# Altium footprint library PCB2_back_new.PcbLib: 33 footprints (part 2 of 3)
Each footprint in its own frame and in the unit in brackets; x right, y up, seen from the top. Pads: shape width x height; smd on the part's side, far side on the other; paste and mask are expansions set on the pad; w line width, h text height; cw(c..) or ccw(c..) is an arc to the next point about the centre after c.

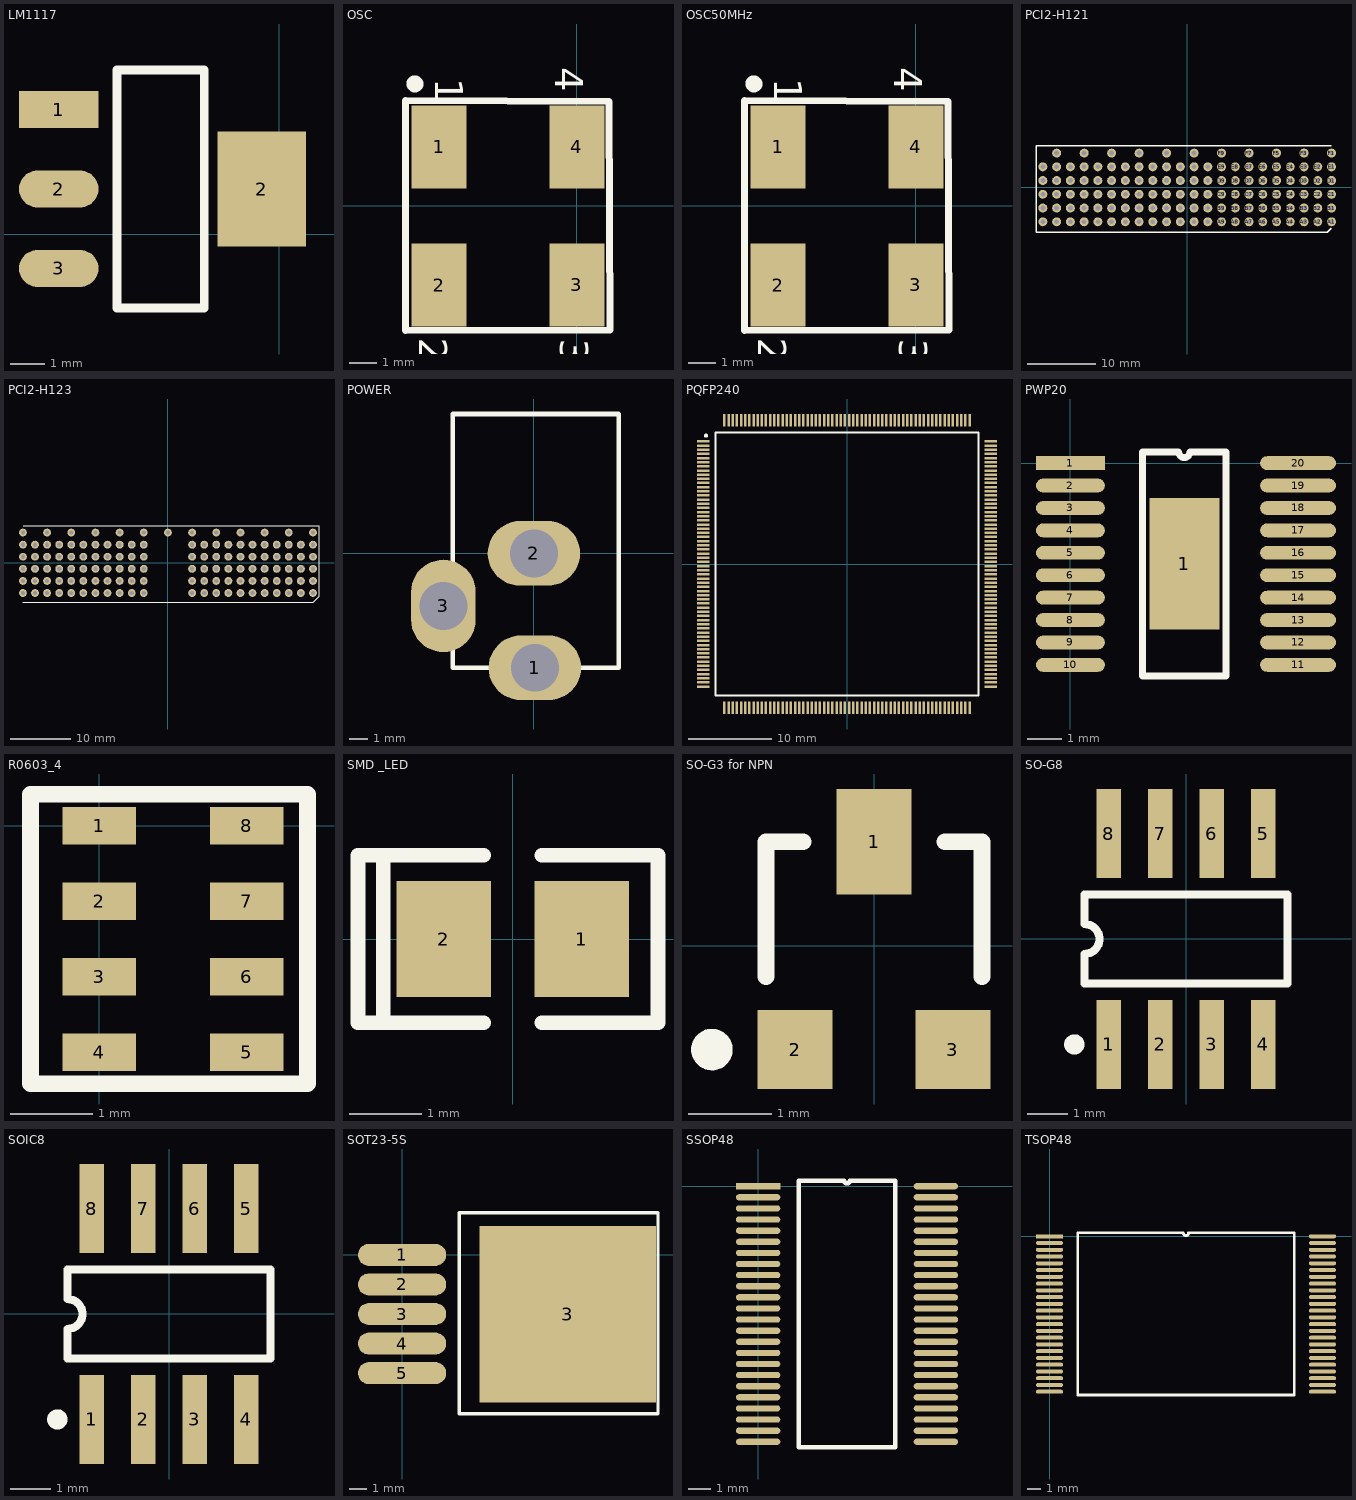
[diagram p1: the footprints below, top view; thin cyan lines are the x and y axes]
## LM1117 [mil]
pads (4):
  rect 90x42 smd: 1(-250,141)
  oval 90x42 smd: 2(-250,51) 3(-250,-39)
  rect 100x130 smd: 2(-20,51)
Top Overlay:
  lines w10: -99,186 -184,186 -184,-84 -85,-84 -85,186 -97.5,186

## OSC [mm]
height 3.5
pads (4):
  rect 2x3 smd: 1(-5,2.134) 2(-5,-2.87) 3(0,-2.866) 4(0,2.134)
Top Overlay:
  circle w0.5: c-5.873,4.42 r0.057
  lines w0.254: -6.223,-4.521 -6.223,3.81 1.168,3.785 1.194,-4.496 -6.223,-4.521
  text "4" at -0.787,5.029 h1.02
  text "3" at -0.61,-4.826 h1.02
  text "2" at -5.715,-4.775 h1.02
  text "1" at -5.131,4.623 h1.02

## OSC50MHz [mm] "for 50MHz"
height 3.5
pads (4):
  rect 2x3 smd: 1(-5,2.134) 2(-5,-2.87) 3(0,-2.866) 4(0,2.134)
Top Overlay:
  circle w0.5: c-5.873,4.42 r0.057
  lines w0.254: -6.223,-4.521 -6.223,3.81 1.168,3.785 1.194,-4.496 -6.223,-4.521
  text "4" at -0.787,5.029 h1.02
  text "3" at -0.61,-4.826 h1.02
  text "2" at -5.715,-4.775 h1.02
  text "1" at -5.131,4.623 h1.02

## PCI2-H121 [mm]
pads (121):
  round 1.3 hole 0.7: A1(21,-5) A2(19,-5) A3(17,-5) A4(15,-5) A5(13,-5) A6(11,-5) A7(9,-5) A8(7,-5) A9(5,-5) A10(3,-5) A11(1,-5) A12(-1,-5) A13(-3,-5) A14(-5,-5) A15(-7,-5) A16(-9,-5) A17(-11,-5) A18(-13,-5) A19(-15,-5) A20(-17,-5) A21(-19,-5) A22(-21,-5) B1(21,-3) B2(19,-3) B3(17,-3) B4(15,-3) B5(13,-3) B6(11,-3) B7(9,-3) B8(7,-3) B9(5,-3) B10(3,-3) B11(1,-3) B12(-1,-3) B13(-3,-3) B14(-5,-3) B15(-7,-3) B16(-9,-3) B17(-11,-3) B18(-13,-3) B19(-15,-3) B20(-17,-3) B21(-19,-3) B22(-21,-3) C1(21,-1) C2(19,-1) C3(17,-1) C4(15,-1) C5(13,-1) C6(11,-1) C7(9,-1) C8(7,-1) C9(5,-1) C10(3,-1) C11(1,-1) C12(-1,-1) C13(-3,-1) C14(-5,-1) C15(-7,-1) C16(-9,-1) C17(-11,-1) C18(-13,-1) C19(-15,-1) C20(-17,-1) C21(-19,-1) C22(-21,-1) D1(21,1) D2(19,1) D3(17,1) D4(15,1) D5(13,1) D6(11,1) D7(9,1) D8(7,1) D9(5,1) D10(3,1) D11(1,1) D12(-1,1) D13(-3,1) D14(-5,1) D15(-7,1) D16(-9,1) D17(-11,1) D18(-13,1) D19(-15,1) D20(-17,1) D21(-19,1) D22(-21,1) E1(21,3) E2(19,3) E3(17,3) E4(15,3) E5(13,3) E6(11,3) E7(9,3) E8(7,3) E9(5,3) E10(3,3) E11(1,3) E12(-1,3) E13(-3,3) E14(-5,3) E15(-7,3) E16(-9,3) E17(-11,3) E18(-13,3) E19(-15,3) E20(-17,3) E21(-19,3) E22(-21,3) F1(21,5) F3(17,5) F5(13,5) F7(9,5) F9(5,5) F11(1,5) F13(-3,5) F15(-7,5) F17(-11,5) F19(-15,5) F21(-19,5)
Top Overlay:
  lines w0.2: 20.371,-6.502 -22,-6.5 -22,6.05 20.93,6.045
  lines w0.203: 20.371,-6.502 20.93,-5.944

## PCI2-H123 [mm]
pads (123):
  round 1.3 hole 0.7: A1(24,-5) A2(22,-5) A3(20,-5) A4(18,-5) A5(16,-5) A6(14,-5) A7(12,-5) A8(10,-5) A9(8,-5) A10(6,-5) A11(4,-5) A15(-4,-5) A16(-6,-5) A17(-8,-5) A18(-10,-5) A19(-12,-5) A20(-14,-5) A21(-16,-5) A22(-18,-5) A23(-20,-5) A24(-22,-5) A25(-24,-5) B1(24,-3) B2(22,-3) B3(20,-3) B4(18,-3) B5(16,-3) B6(14,-3) B7(12,-3) B8(10,-3) B9(8,-3) B10(6,-3) B11(4,-3) B15(-4,-3) B16(-6,-3) B17(-8,-3) B18(-10,-3) B19(-12,-3) B20(-14,-3) B21(-16,-3) B22(-18,-3) B23(-20,-3) B24(-22,-3) B25(-24,-3) C1(24,-1) C2(22,-1) C3(20,-1) C4(18,-1) C5(16,-1) C6(14,-1) C7(12,-1) C8(10,-1) C9(8,-1) C10(6,-1) C11(4,-1) C15(-4,-1) C16(-6,-1) C17(-8,-1) C18(-10,-1) C19(-12,-1) C20(-14,-1) C21(-16,-1) C22(-18,-1) C23(-20,-1) C24(-22,-1) C25(-24,-1) D1(24,1) D2(22,1) D3(20,1) D4(18,1) D5(16,1) D6(14,1) D7(12,1) D8(10,1) D9(8,1) D10(6,1) D11(4,1) D15(-4,1) D16(-6,1) D17(-8,1) D18(-10,1) D19(-12,1) D20(-14,1) D21(-16,1) D22(-18,1) D23(-20,1) D24(-22,1) D25(-24,1) E1(24,3) E2(22,3) E3(20,3) E4(18,3) E5(16,3) E6(14,3) E7(12,3) E8(10,3) E9(8,3) E10(6,3) E11(4,3) E15(-4,3) E16(-6,3) E17(-8,3) E18(-10,3) E19(-12,3) E20(-14,3) E21(-16,3) E22(-18,3) E23(-20,3) E24(-22,3) E25(-24,3) F1(24,5) F3(20,5) F5(16,5) F7(12,5) F9(8,5) F11(4,5) F13(0,5) F15(-4,5) F17(-8,5) F19(-12,5) F21(-16,5) F23(-20,5) F25(-24,5)
Top Overlay:
  lines w0.2: -24.028,-6.502 24.028,-6.5 25,-5.528 25,6.1 -23.978,6.096
  lines w0.203: 24.028,-6.5 25,-5.528 25,-5.283

## POWER [mil]
pads (3):
  oval 197x138 hole 102: 1(2.16,-244.32) 2(0.16,-0.32)
  oval 138x197 hole 102: 3(-192.84,-112.32)
Top Overlay:
  lines w10: -172.84,-244.32 -172.84,296.68 181.16,296.68 181.16,-244.32 -170.84,-244.32

## PQFP240 [mm] "byTX chaned for cyclone FPGA"
pads (240):
  rect 1.5x0.3 smd: 1(-17.3,14.75) 2(-17.3,14.25) 3(-17.3,13.75) 4(-17.3,13.25) 5(-17.3,12.75) 6(-17.3,12.25) 7(-17.3,11.75) 8(-17.3,11.25) 9(-17.3,10.75) 10(-17.3,10.25) 11(-17.3,9.75) 12(-17.3,9.25) 13(-17.3,8.75) 14(-17.3,8.25) 15(-17.3,7.75) 16(-17.3,7.25) 17(-17.3,6.75) 18(-17.3,6.25) 19(-17.3,5.75) 20(-17.3,5.25) 21(-17.3,4.75) 22(-17.3,4.25) 23(-17.3,3.75) 24(-17.3,3.25) 25(-17.3,2.75) 26(-17.3,2.25) 27(-17.3,1.75) 28(-17.3,1.25) 29(-17.3,0.75) 30(-17.3,0.25) 31(-17.3,-0.25) 32(-17.3,-0.75) 33(-17.3,-1.25) 34(-17.3,-1.75) 35(-17.3,-2.25) 36(-17.3,-2.75) 37(-17.3,-3.25) 38(-17.3,-3.75) 39(-17.3,-4.25) 40(-17.3,-4.75) 41(-17.3,-5.25) 42(-17.3,-5.75) 43(-17.3,-6.25) 44(-17.3,-6.75) 45(-17.3,-7.25) 46(-17.3,-7.75) 47(-17.3,-8.25) 48(-17.3,-8.75) 49(-17.3,-9.25) 50(-17.3,-9.75) 51(-17.3,-10.25) 52(-17.3,-10.75) 53(-17.3,-11.25) 54(-17.3,-11.75) 55(-17.3,-12.25) 56(-17.3,-12.75) 57(-17.3,-13.25) 58(-17.3,-13.75) 59(-17.3,-14.25) 60(-17.3,-14.75) 121(17.3,-14.75) 122(17.3,-14.25) 123(17.3,-13.75) 124(17.3,-13.25) 125(17.3,-12.75) 126(17.3,-12.25) 127(17.3,-11.75) 128(17.3,-11.25) 129(17.3,-10.75) 130(17.3,-10.25) 131(17.3,-9.75) 132(17.3,-9.25) 133(17.3,-8.75) 134(17.3,-8.25) 135(17.3,-7.75) 136(17.3,-7.25) 137(17.3,-6.75) 138(17.3,-6.25) 139(17.3,-5.75) 140(17.3,-5.25) 141(17.3,-4.75) 142(17.3,-4.25) 143(17.3,-3.75) 144(17.3,-3.25) 145(17.3,-2.75) 146(17.3,-2.25) 147(17.3,-1.75) 148(17.3,-1.25) 149(17.3,-0.75) 150(17.3,-0.25) 151(17.3,0.25) 152(17.3,0.75) 153(17.3,1.25) 154(17.3,1.75) 155(17.3,2.25) 156(17.3,2.75) 157(17.3,3.25) 158(17.3,3.75) 159(17.3,4.25) 160(17.3,4.75) 161(17.3,5.25) 162(17.3,5.75) 163(17.3,6.25) 164(17.3,6.75) 165(17.3,7.25) 166(17.3,7.75) 167(17.3,8.25) 168(17.3,8.75) 169(17.3,9.25) 170(17.3,9.75) 171(17.3,10.25) 172(17.3,10.75) 173(17.3,11.25) 174(17.3,11.75) 175(17.3,12.25) 176(17.3,12.75) 177(17.3,13.25) 178(17.3,13.75) 179(17.3,14.25) 180(17.3,14.75)
  rect 0.3x1.5 smd: 61(-14.75,-17.3) 62(-14.25,-17.3) 63(-13.75,-17.3) 64(-13.25,-17.3) 65(-12.75,-17.3) 66(-12.25,-17.3) 67(-11.75,-17.3) 68(-11.25,-17.3) 69(-10.75,-17.3) 70(-10.25,-17.3) 71(-9.75,-17.3) 72(-9.25,-17.3) 73(-8.75,-17.3) 74(-8.25,-17.3) 75(-7.75,-17.3) 76(-7.25,-17.3) 77(-6.75,-17.3) 78(-6.25,-17.3) 79(-5.75,-17.3) 80(-5.25,-17.3) 81(-4.75,-17.3) 82(-4.25,-17.3) 83(-3.75,-17.3) 84(-3.25,-17.3) 85(-2.75,-17.3) 86(-2.25,-17.3) 87(-1.75,-17.3) 88(-1.25,-17.3) 89(-0.75,-17.3) 90(-0.25,-17.3) 91(0.25,-17.3) 92(0.75,-17.3) 93(1.25,-17.3) 94(1.75,-17.3) 95(2.25,-17.3) 96(2.75,-17.3) 97(3.25,-17.3) 98(3.75,-17.3) 99(4.25,-17.3) 100(4.75,-17.3) 101(5.25,-17.3) 102(5.75,-17.3) 103(6.25,-17.3) 104(6.75,-17.3) 105(7.25,-17.3) 106(7.75,-17.3) 107(8.25,-17.3) 108(8.75,-17.3) 109(9.25,-17.3) 110(9.75,-17.3) 111(10.25,-17.3) 112(10.75,-17.3) 113(11.25,-17.3) 114(11.75,-17.3) 115(12.25,-17.3) 116(12.75,-17.3) 117(13.25,-17.3) 118(13.75,-17.3) 119(14.25,-17.3) 120(14.75,-17.3) 181(14.75,17.3) 182(14.25,17.3) 183(13.75,17.3) 184(13.25,17.3) 185(12.75,17.3) 186(12.25,17.3) 187(11.75,17.3) 188(11.25,17.3) 189(10.75,17.3) 190(10.25,17.3) 191(9.75,17.3) 192(9.25,17.3) 193(8.75,17.3) 194(8.25,17.3) 195(7.75,17.3) 196(7.25,17.3) 197(6.75,17.3) 198(6.25,17.3) 199(5.75,17.3) 200(5.25,17.3) 201(4.75,17.3) 202(4.25,17.3) 203(3.75,17.3) 204(3.25,17.3) 205(2.75,17.3) 206(2.25,17.3) 207(1.75,17.3) 208(1.25,17.3) 209(0.75,17.3) 210(0.25,17.3) 211(-0.25,17.3) 212(-0.75,17.3) 213(-1.25,17.3) 214(-1.75,17.3) 215(-2.25,17.3) 216(-2.75,17.3) 217(-3.25,17.3) 218(-3.75,17.3) 219(-4.25,17.3) 220(-4.75,17.3) 221(-5.25,17.3) 222(-5.75,17.3) 223(-6.25,17.3) 224(-6.75,17.3) 225(-7.25,17.3) 226(-7.75,17.3) 227(-8.25,17.3) 228(-8.75,17.3) 229(-9.25,17.3) 230(-9.75,17.3) 231(-10.25,17.3) 232(-10.75,17.3) 233(-11.25,17.3) 234(-11.75,17.3) 235(-12.25,17.3) 236(-12.75,17.3) 237(-13.25,17.3) 238(-13.75,17.3) 239(-14.25,17.3) 240(-14.75,17.3)
Top Overlay:
  circle w0.25: c-16.975,15.45 r0.125
  lines w0.2: -15.825,-15.825 -15.825,15.825 15.825,15.825 15.825,-15.825 -15.825,-15.825

## PWP20 [mm] "PWP20;PSO;PWP (R-PDSO-G**);for TPS54310"
height 3.5
pads (21):
  rect 2x0.4 smd: 1(0,0)
  rect 2.032x3.81 smd: 1(3.302,-2.921)
  oval 2x0.4 smd: 2(0,-0.65) 3(0,-1.3) 4(0,-1.95) 5(0,-2.6) 6(0,-3.25) 7(0,-3.9) 8(0,-4.55) 9(0,-5.2) 10(0,-5.85)
  oval 2.2x0.4 smd: 11(6.6,-5.85) 12(6.6,-5.2) 13(6.6,-4.55) 14(6.6,-3.9) 15(6.6,-3.25) 16(6.6,-2.6) 17(6.6,-1.95) 18(6.6,-1.3) 19(6.6,-0.65) 20(6.6,0)
Top Overlay:
  lines w0.2: 2.085,-6.175 2.085,0.325 3.137,0.325 ccw(c3.3,0.325) 3.462,0.325 4.515,0.325 4.515,-6.175 2.085,-6.175
Top Paste:
  rectangle: 2.286,-4.318 4.318,-1.524

## R0603_4 [mil] "for ResPackX4____OK!"
height 137.79
pads (8):
  rect 35x18 smd: 1(0,0) 2(0,-36) 3(0,-72) 4(0,-108) 5(70.16,-108) 6(70.16,-72) 7(70.16,-36) 8(70.16,0)
Top Overlay:
  lines w8: -32.84,15 -32.84,-123 99.16,-123 99.16,15 -31.84,15

## SMD _LED [mm]
height 3.5
pads (2):
  rect 1.3x1.6 smd: 1(0.95,0) 2(-0.95,0)
Top Overlay:
  lines w0.2: -1.78,-1.15 -1.78,1.15 ; -0.4,-1.15 -2.13,-1.15 -2.13,1.15 -0.4,1.15 ; 0.4,-1.15 2,-1.15 2,1.15 0.4,1.15

## SO-G3 for NPN [mm]
height 3.5
pads (3):
  rect 0.9x1.27 smd: 1(0,1.25)
  rect 0.9x0.95 smd: 2(-0.95,-1.25) 3(0.95,-1.25)
Top Overlay:
  circle w0.25: c-1.95,-1.25 r0.125
  lines w0.2: -1.3,-0.375 -1.3,1.25 -0.85,1.25 ; 0.85,1.25 1.3,1.25 1.3,-0.375

## SO-G8 [mm]
height 3.5
pads (8):
  rect 0.6x2.2 smd: 1(-1.905,-2.6) 2(-0.635,-2.6) 3(0.635,-2.6) 4(1.905,-2.6) 5(1.905,2.6) 6(0.635,2.6) 7(-0.635,2.6) 8(-1.905,2.6)
Top Overlay:
  circle w0.25: c-2.755,-2.6 r0.125
  lines w0.2: -2.5,-1.1 -2.5,-0.367 ccw(c-2.5,0) -2.5,0.367 -2.5,1.1 2.5,1.1 2.5,-1.1 -2.5,-1.1

## SOIC8 [mm] "8-Pin Small-Outline Integrated Circuit (SOIC)"
height 1.75
pads (8):
  rect 0.6x2.2 smd: 1(-1.905,-2.6) 2(-0.635,-2.6) 3(0.635,-2.6) 4(1.905,-2.6) 5(1.905,2.6) 6(0.635,2.6) 7(-0.635,2.6) 8(-1.905,2.6)
Top Overlay:
  circle w0.25: c-2.755,-2.6 r0.125
  lines w0.2: -2.5,-1.1 -2.5,-0.367 ccw(c-2.5,0) -2.5,0.367 -2.5,1.1 2.5,1.1 2.5,-1.1 -2.5,-1.1

## SOT23-5S [mil] "for TPS75733"
pads (6):
  oval 200x50 smd: 1(0,0) 2(0,-67) 3(0,-134) 4(0,-201) 5(0,-268)
  rect 400x400 smd: 3(375,-135)
Top Overlay:
  lines w7.87: 130,-360 130,95 580,95 580,-360 130,-360

## SSOP48 [mm]
pads (48):
  rect 2x0.28 smd: 1(0,0)
  oval 2x0.28 smd: 2(0,-0.5) 3(0,-1) 4(0,-1.5) 5(0,-2) 6(0,-2.5) 7(0,-3) 8(0,-3.5) 9(0,-4) 10(0,-4.5) 11(0,-5) 12(0,-5.5) 13(0,-6) 14(0,-6.5) 15(0,-7) 16(0,-7.5) 17(0,-8) 18(0,-8.5) 19(0,-9) 20(0,-9.5) 21(0,-10) 22(0,-10.5) 23(0,-11) 24(0,-11.5) 25(8,-11.5) 26(8,-11) 27(8,-10.5) 28(8,-10) 29(8,-9.5) 30(8,-9) 31(8,-8.5) 32(8,-8) 33(8,-7.5) 34(8,-7) 35(8,-6.5) 36(8,-6) 37(8,-5.5) 38(8,-5) 39(8,-4.5) 40(8,-4) 41(8,-3.5) 42(8,-3) 43(8,-2.5) 44(8,-2) 45(8,-1.5) 46(8,-1) 47(8,-0.5) 48(8,0)
Top Overlay:
  lines w0.2: 1.835,-11.75 6.165,-11.75 6.165,0.25 4.125,0.25 cw(c4,0.25) 3.875,0.25 1.835,0.25 1.835,-11.75

## TSOP48 [mm] "for Am29LV800B"
pads (48):
  rect 2x0.3 smd: 1(0,0)
  oval 2x0.3 smd: 2(0,-0.5) 3(0,-1) 4(0,-1.5) 5(0,-2) 6(0,-2.5) 7(0,-3) 8(0,-3.5) 9(0,-4) 10(0,-4.5) 11(0,-5) 12(0,-5.5) 13(0,-6) 14(0,-6.5) 15(0,-7) 16(0,-7.5) 17(0,-8) 18(0,-8.5) 19(0,-9) 20(0,-9.5) 21(0,-10) 22(0,-10.5) 23(0,-11) 24(0,-11.5) 25(20.2,-11.5) 26(20.2,-11) 27(20.2,-10.5) 28(20.2,-10) 29(20.2,-9.5) 30(20.2,-9) 31(20.2,-8.5) 32(20.2,-8) 33(20.2,-7.5) 34(20.2,-7) 35(20.2,-6.5) 36(20.2,-6) 37(20.2,-5.5) 38(20.2,-5) 39(20.2,-4.5) 40(20.2,-4) 41(20.2,-3.5) 42(20.2,-3) 43(20.2,-2.5) 44(20.2,-2) 45(20.2,-1.5) 46(20.2,-1) 47(20.2,-0.5) 48(20.2,0)
Top Overlay:
  lines w0.2: 9.9,0.25 ccw(c10.1,0.25) 10.3,0.25 ; 9.906,0.254 2.085,0.25 2.085,-11.75 18.115,-11.75 18.115,0.25 10.287,0.254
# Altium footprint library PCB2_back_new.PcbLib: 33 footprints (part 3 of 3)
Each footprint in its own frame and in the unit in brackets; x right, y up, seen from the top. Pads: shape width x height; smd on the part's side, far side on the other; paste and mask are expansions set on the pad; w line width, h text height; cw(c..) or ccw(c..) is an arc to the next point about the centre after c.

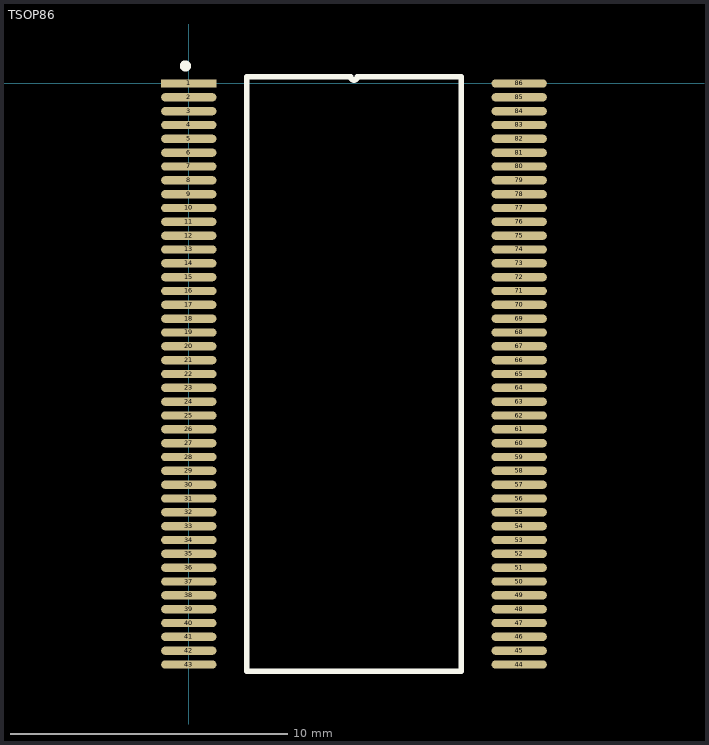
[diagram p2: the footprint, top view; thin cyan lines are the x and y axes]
## TSOP86 [mm] "TSOP;43*2;for HY57V283220"
pads (86):
  rect 2x0.3 smd: 1(0,0)
  oval 2x0.3 smd: 2(0,-0.5) 3(0,-1) 4(0,-1.5) 5(0,-2) 6(0,-2.5) 7(0,-3) 8(0,-3.5) 9(0,-4) 10(0,-4.5) 11(0,-5) 12(0,-5.5) 13(0,-6) 14(0,-6.5) 15(0,-7) 16(0,-7.5) 17(0,-8) 18(0,-8.5) 19(0,-9) 20(0,-9.5) 21(0,-10) 22(0,-10.5) 23(0,-11) 24(0,-11.5) 25(0,-12) 26(0,-12.5) 27(0,-13) 28(0,-13.5) 29(0,-14) 30(0,-14.5) 31(0,-15) 32(0,-15.5) 33(0,-16) 34(0,-16.5) 35(0,-17) 36(0,-17.5) 37(0,-18) 38(0,-18.5) 39(0,-19) 40(0,-19.5) 41(0,-20) 42(0,-20.5) 43(0,-21) 44(11.938,-21) 45(11.938,-20.5) 46(11.938,-20) 47(11.938,-19.5) 48(11.938,-19) 49(11.938,-18.5) 50(11.938,-18) 51(11.938,-17.5) 52(11.938,-17) 53(11.938,-16.5) 54(11.938,-16) 55(11.938,-15.5) 56(11.938,-15) 57(11.938,-14.5) 58(11.938,-14) 59(11.938,-13.5) 60(11.938,-13) 61(11.938,-12.5) 62(11.938,-12) 63(11.938,-11.5) 64(11.938,-11) 65(11.938,-10.5) 66(11.938,-10) 67(11.938,-9.5) 68(11.938,-9) 69(11.938,-8.5) 70(11.938,-8) 71(11.938,-7.5) 72(11.938,-7) 73(11.938,-6.5) 74(11.938,-6) 75(11.938,-5.5) 76(11.938,-5) 77(11.938,-4.5) 78(11.938,-4) 79(11.938,-3.5) 80(11.938,-3) 81(11.938,-2.5) 82(11.938,-2) 83(11.938,-1.5) 84(11.938,-1) 85(11.938,-0.5) 86(11.938,0)
Top Overlay:
  circle w0.2: c-0.125,0.635 r0.1
  lines w0.2: 2.085,-21.25 9.853,-21.25 9.853,0.25 6.094,0.25 cw(c5.969,0.25) 5.844,0.25 2.085,0.25 2.085,-21.25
